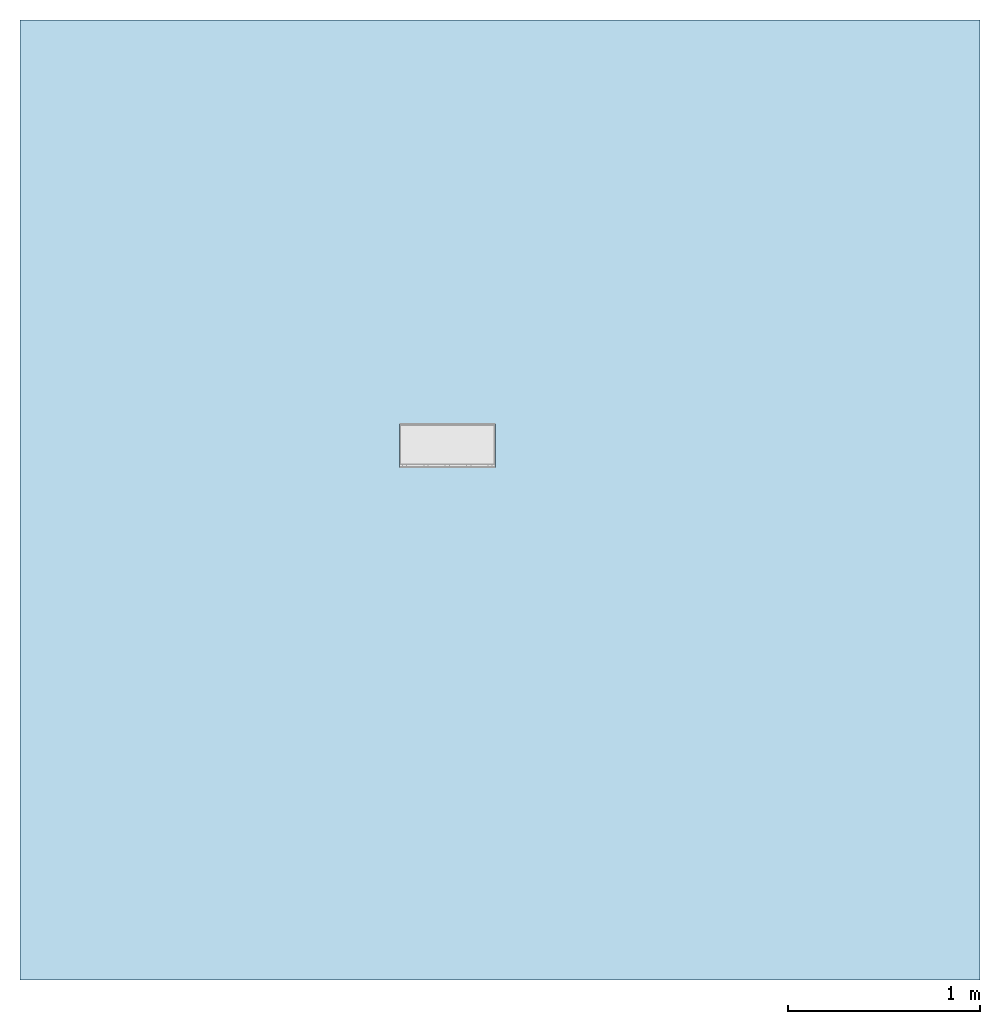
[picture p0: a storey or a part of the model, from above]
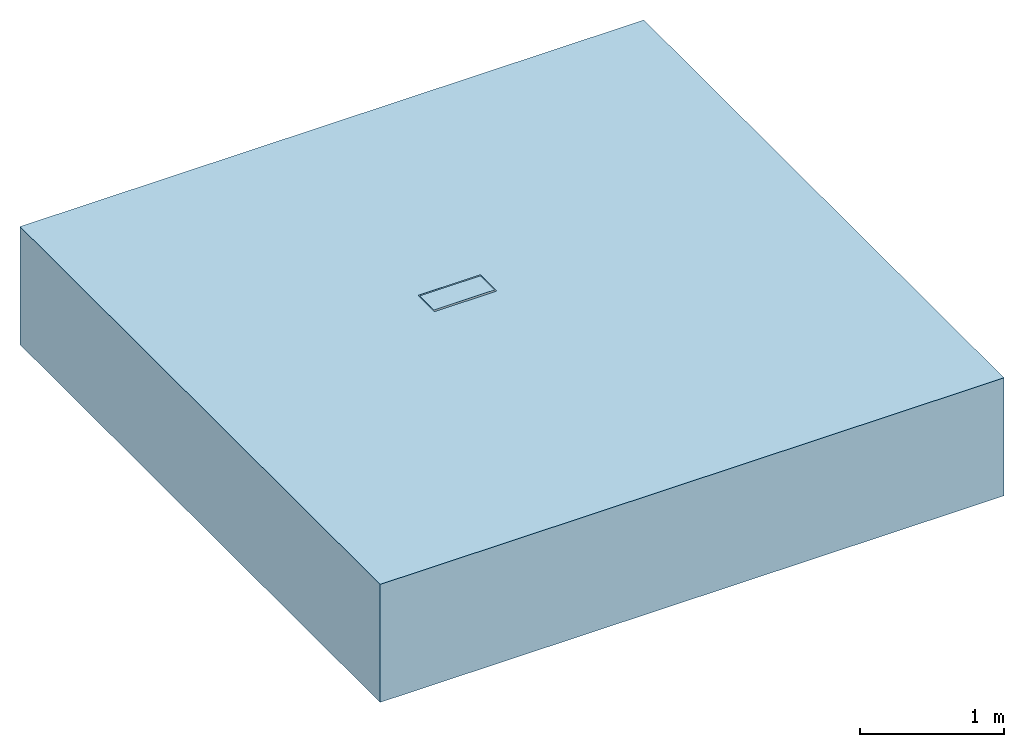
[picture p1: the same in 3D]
Properties of the parts of a building model (IFC2X3)

# File
Description: ViewDefinition [CoordinationView]
File name: 24218 - Universal Sump Unit - 500mm LG.ifc
Time: 2013-10-30T14:18:02
Written by: Autodesk Revit 2013
Made in: 20120221_2030(x64)

# IfcProject, Project Number
LongName: Project Name; Phase: Project Status

# IfcSite, Default
RefLatitude: 42, 21, 30, 344238; RefLongitude: -71, -3, -35, -194702; RefElevation: 0 mm

# IfcBuilding
Pset_BuildingCommon - NumberOfStoreys: 1
Other - Project Issue Date: Issue Date; Project Number: Project Number; Client Name: Owner; Project Name: Project Name; Project Status: Project Status; Project Address: ## Street City, State Zip

# IfcBuildingStorey, Level 1
LongName: Level 1; Elevation: 0 mm
Constraints - Elevation Base: 0; Elevation: 0 mm
Graphics - Color: 0; Symbol at End 2 Default: yes; Line Pattern: Center; Symbol at End 1 Default: no; Symbol: M_Level Head - Circle: M_Level Head - Circle; Line Weight: 1
Identity Data - Building Story: yes; Name: Level 1; Structural: no
Dimensions - Computation Height: 0 mm

# IfcBuildingElementProxy: 24218 - Universal Sump Unit - 500mm LG, Civil-Drainage-Channel-ACO-MultiDrain-M200DS-Brickslot-Channel-System:24218 - Universal Sump Unit - 500mm LG:24218 - Universal Sump Unit - 500mm LG:196059
In: Level 1
Material: Stainless Steel (F), Phenolic Resin, Plastic, Opaque Black, Vienite® Synthetic Resin Concrete
Data - Load Class: A 15 - D 400; Invert Depth: 765mm; Product Standard: BS EN 1433:2002, CE marked; Concrete Surround Volume - Load Class B 125 - C 250 - Concrete Pavement: N/A; Concrete Surround Volume - Load Class A 15 - Concrete Pavement: N/A; Product Weight: 48.0 Kg; Installation - Concrete Grade: Refer to brochure; Channel C.S.A: N/A; ACO Hydraulic Design Software: http://www.acodesign.co.uk; Hydraulic Performance: http://www.aco.co.uk/download.php?id=173; Product Dimensions: 500mm x 235mm x 790mm (LxWxH); Concrete Surround Volume - Load Class D 400 - Concrete Pavement: N/A
Dimensions - Brickslot Access Unit Void Depth: 0 mm; Brickslot Void Length: 500 mm; Brickslot Grating Void Depth: 6500 mm; EndCap Position: 500 mm; FloorCut_Length: -500 mm; Volume: 23569804 mm3; Brickslot Access Unit Void Bottom Depth: 105 mm; Length: 1000 mm; Custom_Void_Length: 500 mm; Length Drain: -1000 mm; InvDepth: 110 mm; FloorCut_HorPosition: 117.5 mm; EndCap_Height: 310 mm; Depth: 235 mm; FloorCut_Width: 235 mm; FloorCut_Depth: 790 mm
Construction - 23219 - Universal Endcap (Male End): no; 409000_Load Class C250 & D400_Brickslot_Access Unit_Stainless Steel_500mm Long: yes; 408999_Load Class C250 & D400_Brickslot Grating_Stainless Steel_500mm Long: no; 23219 - Universal Endcap (Female End): no; 408998_Load Class C250 & D400_Brickslot Grating_Stainless Steel_1000mm Long: no; Shallow Depth Channel: no; Constant Depth Channel_500: no; Constant Depth Channel_1000: no; Shallow Depth Channel with seal: no; 23410_Sump Unit: yes
Phasing - Phase Created: New Construction
Constraints - Moves With Nearby Elements: no; Level: Level: Level 1
Pset_BuildingElementProxyCommon - Reference: 24218 - Universal Sump Unit - 500mm LG
Green Building Properties - Channel Recycled Material Content: 20% minimum; Channel Recyclable: Fully recyclable; Edge Rail Recyclable: Fully recyclable; Edge Rail Recycled Material Content: Between 40% - 90%
Identity Data - Model: ACO MultiDrain MDS Brickslot - M200DS; Manufacturer: ACO Technologies plc - ACO Water Management Division; Product Code: 24218; Model Description: Channel drainage system; Watermarked With: BIM Manager Premium Suite; Type Comments: ACO MultiDrain M200DS Sump Unit 500mm Long; Watermark 1: This file is the property of ACO Technologies PLC; OmniClass Number: 23.70.50.24; Telephone: +44 (0)1462 816666; URL: www.aco.co.uk; Assembly Code: D2040; Price: POA - contact ACO; e-mail Technical: technical@aco.co.uk; Assembly Description: Rain Water Drainage; Product Page URL: http://www.aco.co.uk/product_detail.php?id=58; Watermark 2: This file is water marked and users are prohibited to reproduce, adapt, distribute this information; Maintenance guidelines: http://www.aco.co.uk/download.php?id=173; Watermarked By: www.aco.co.uk; Address: ACO Business Park, Hitchin Road, Shefford, Bedfordshire, United Kingdom SG17 5TE; e-mail Sales: customersupport@aco.co.uk; Product brochure: http://www.aco.co.uk/download.php?id=173; Cost: 0; OmniClass Title: Rainwater Removal; Fax: +44 (0)1462 815895; Installation guidelines: http://www.aco.co.uk/download.php?id=173
General - SerialNumber: 0; TagNumber: 0
Materials and Finishes - Channel Material: Vienite® Synthetic Resin Concrete; Channel Colour: Brown; Edge Rail Colour: Self; Edge Rail Material: Stainless Steel Grade 304
Model Properties - Brickslot Access Unit Product code 409000: Load Class C250/D400 - Brickslot Access Unit Stainless Steel - 500mm long x 105mm high - 10mm Slot - Intake area 10000mm²/m - 8.5 Kg; Brickslot Grating Product code 408998: N/A; End Cap Product code 23219: N/A; Brickslot Grating Product code 408999: N/A
Other - Revision: 1; CreatedBy: www.aco.co.uk

# IfcOpeningElement: Recess (2)
In: Level 1
Dimensions - Area: 25000000 mm2; Thickness: 1000 mm; Perimeter: 20000 mm; Volume: 24905454890 mm3
Constraints - Related to Mass: no; Level: Level: Level 1; Room Bounding: yes; Height Offset From Level: 0 mm
Structural - Enable Analytical Model: no; Structural: no
Phasing - Phase Created: New Construction
Analytical Properties - Heat Transfer Coefficient (U): 0.837; Thermal Resistance (R): 1.19474; Absorptance: 0.1; Thermal mass: 1359800; Roughness: 1
Construction - Function: 0; Default Thickness: 1000 mm
Materials and Finishes - Structural Material: Earth
Graphics - Coarse Scale Fill Color: 0

# IfcSlab: Floor:Generic Floor - 1000mm, Floor:Generic Floor - 1000mm:193825
In: Level 1
PredefinedType: FLOOR; Material: Earth 1000 mm
Dimensions - Area: 25000000 mm2; Thickness: 1000 mm; Perimeter: 20000 mm; Volume: 24905454890 mm3
Constraints - Related to Mass: no; Level: Level: Level 1; Room Bounding: yes; Height Offset From Level: 0 mm
Structural - Enable Analytical Model: no; Structural: no
Phasing - Phase Created: New Construction
Pset_SlabCommon - Reference: Generic Floor - 1000mm; IsExternal: no; LoadBearing: yes
Analytical Properties - Heat Transfer Coefficient (U): 0.837; Thermal Resistance (R): 1.19474; Absorptance: 0.1; Thermal mass: 1359800; Roughness: 1
Construction - Function: 0; Default Thickness: 1000 mm
Materials and Finishes - Structural Material: Earth
Graphics - Coarse Scale Fill Color: 0
